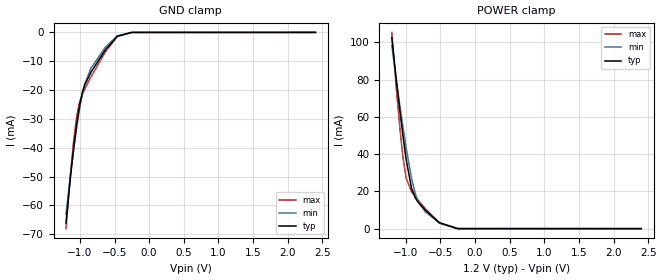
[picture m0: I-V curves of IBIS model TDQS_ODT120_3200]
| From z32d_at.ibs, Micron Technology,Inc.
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| MODEL TDQS_ODT120_3200 (TDQS Terminator Model with 120ohm ODT, 1600-3200Mbps)
[Model]   TDQS_ODT120_3200
Model_type   Terminator
|   typ   min   max
|C_comp   0.616pF   0.564pF   0.668pF
C_comp_power_clamp   0.308pF   0.282pF   0.334pF
C_comp_gnd_clamp   0.308pF   0.282pF   0.334pF
| Note: C_comp changes when the ODT circuit is enabled.
[Voltage Range]   1.2000V   1.1400V   1.2600V
| Junction Temperature (Ambient temp is 35C typ, 105C min, -40C max)
[Temperature Range]   50.0   120.0   -40.0
[Add Submodel]
| Submodel Name   Mode
120ohm_ODT_3200   Non-Driving
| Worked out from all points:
|   GND clamp passes 1 mA (typ) near -0.44 V on its own axis
|   POWER clamp passes 1 mA (typ) near -0.41 V on its own axis
[GND Clamp]
|   Voltage   I(typ)   I(min)   I(max)
-1.2V     -66.16mA   -63.19mA   -68.09mA
-1.135V   -50.09mA   -49.27mA   -48.84mA
-1.091V   -40.54mA   -40.91mA   -37.85mA
-1.047V   -32.06mA   -33.18mA   -29.28mA
-1.004V   -25.24mA   -26.41mA   -24.15mA
-960mV    -20.46mA   -20.87mA   -21.27mA
-927.3mV  -18.11mA   -17.71mA   -19.59mA
-840mV    -13.84mA   -12.43mA   -15.5mA
-632.7mV  -6.06mA    -5.168mA   -6.758mA
-458.2mV  -1.359mA   -1.153mA   -1.332mA
-250.9mV  -9.002uA   -15.24uA   1.741uA
2.4V      0A         0A         0A
[POWER Clamp]
|   Voltage   I(typ)   I(min)   I(max)
-1.2V     102.5mA    98.29mA    105.3mA
-1.135V   79.77mA    79.49mA    75.19mA
-1.08V    62.13mA    64.93mA    52.54mA
-1.036V   48.91mA    53.79mA    37.32mA
-992.7mV  37.04mA    43.27mA    27.02mA
-916.4mV  21.89mA    27.24mA    20mA
-861.8mV  16.57mA    18.83mA    17.26mA
-818.2mV  14.14mA    14.37mA    15.22mA
-720mV    10.08mA    9.153mA    10.86mA
-512.7mV  3.198mA    2.931mA    3.061mA
-250.9mV  21.9uA     40.66uA    -1.736uA
2.4V      0A         0A         0A
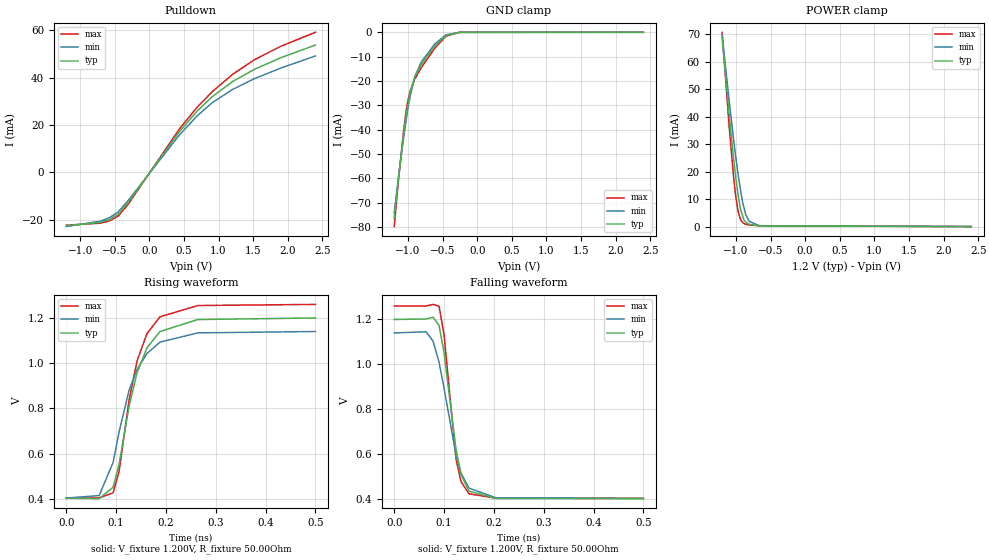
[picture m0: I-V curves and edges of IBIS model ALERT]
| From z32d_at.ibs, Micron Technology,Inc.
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| MODEL ALERT (ALERT_n Output Model, 1600-3200Mbps)
[Model]   ALERT
Model_type   Open_sink
Vmeas = 960.000mV
Vref = 1200.000mV
Cref = 0.0pF
Rref = 50.000Ohm
|   typ   min   max
|C_comp   0.610pF   0.560pF   0.660pF
C_comp_pulldown   0.610pF   0.560pF   0.660pF
[Model Spec]
| Timing spec test load voltage corners
Vref   1.2000V   1.1400V   1.2600V
[Voltage Range]   1.2000V   1.1400V   1.2600V
| Junction Temperature (Ambient temp is 35C typ, 105C min, -40C max)
[Temperature Range]   50.0   120.0   -40.0
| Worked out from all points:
|   slope of the pulldown table from 0 to 0.18 V, typ, clamps not added: 24.5 ohm
|   GND clamp passes 1 mA (typ) near -0.43 V on its own axis
|   POWER clamp passes 1 mA (typ) near -0.83 V on its own axis
|   falling waveform, V_fixture 1.200V, R_fixture 50.00Ohm: 20-80 % time 27.9ps typ, 37.5ps min, 22.3ps max; typ from 1.2 V to 0.402 V
|   rising waveform, V_fixture 1.200V, R_fixture 50.00Ohm: 20-80 % time 49.1ps typ, 53.8ps min, 43.7ps max; typ from 0.402 V to 1.2 V
[Pulldown]
|   Voltage   I(typ)   I(min)   I(max)
-1.2V     -22.54mA   -22.87mA   -22.27mA
-710mV    -21.12mA   -20.6mA    -21.46mA
-570mV    -19.84mA   -19.05mA   -20.41mA
-450mV    -17.65mA   -16.68mA   -18.44mA
-310mV    -12.89mA   -12.03mA   -13.65mA
435mV     17.19mA    15.81mA    18.36mA
690mV     25.85mA    23.84mA    27.49mA
910mV     31.97mA    29.44mA    34.06mA
1.205V    38.38mA    35.04mA    41.41mA
1.52V     43.52mA    39.57mA    47.57mA
1.905V    48.45mA    44.09mA    53.3mA
2.4V      53.74mA    49.14mA    59.12mA
[GND Clamp]
|   Voltage   I(typ)   I(min)   I(max)
-1.2V     -76.4mA    -74.25mA   -79.84mA
-1.135V   -59.09mA   -58.98mA   -59.82mA
-1.07V    -43.25mA   -44.67mA   -41.91mA
-1.035V   -35.61mA   -37.58mA   -33.91mA
-1.005V   -30.19mA   -31.98mA   -28.51mA
-970mV    -24.78mA   -26.43mA   -24.09mA
-905mV    -18.52mA   -18.41mA   -19.37mA
-810mV    -13.26mA   -12.25mA   -14.58mA
-615mV    -5.667mA   -4.803mA   -6.603mA
-450mV    -1.266mA   -1.025mA   -1.56mA
-255mV    -15.46uA   -18.56uA   -16.29uA
2.4V      0A         0A         0A
[POWER Clamp]
|   Voltage   I(typ)   I(min)   I(max)
-1.2V     68.86mA    69.95mA    70.72mA
-1.1V     41.05mA    46.24mA    36.96mA
-1.035V   24.8mA     31.9mA     18.19mA
-1.005V   18.35mA    25.71mA    11.33mA
-970mV    11.69mA    19.19mA    5.58mA
-935mV    6.43mA     13.41mA    2.598mA
-905mV    3.96mA     8.987mA    1.451mA
-885mV    2.429mA    6.991mA    1.136mA
-860mV    1.707mA    4.496mA    842.7uA
-810mV    801.4uA    1.92mA     564uA
-660mV    241.9uA    277.1uA    324.3uA
2.4V      0A         0A         0A
[Ramp]
R_load = 50.00Ohm
|   typ   min   max
dV/dt_r   478.729mV/49.051ps  442.085mV/53.817ps  513.741mV/43.654ps
dV/dt_f   478.729mV/27.886ps  442.085mV/37.537ps  513.741mV/22.329ps
[Falling Waveform]
V_fixture = 1.200V
V_fixture_min = 1.140V
V_fixture_max = 1.260V
R_fixture = 50.00Ohm
|   Time   V(typ)   V(min)   V(max)
0s        1.2V       1.14V      1.26V
64ps      1.202V     1.145V     1.26V
78ps      1.21V      1.103V     1.267V
90ps      1.173V     1.01V      1.259V
100ps     1.053V     894.4mV    1.132V
124ps     621.8mV    597mV      579.3mV
134ps     509.7mV    516.3mV    478.1mV
150ps     436mV      449.3mV    423.8mV
204ps     403.2mV    406.2mV    404.1mV
500ps     402.1mV    403.2mV    403.8mV
[Rising Waveform]
V_fixture = 1.200V
V_fixture_min = 1.140V
V_fixture_max = 1.260V
R_fixture = 50.00Ohm
|   Time   V(typ)   V(min)   V(max)
0s        402.1mV    403.2mV    403.8mV
66ps      400.3mV    414mV      403.3mV
94ps      451.1mV    560.8mV    426.5mV
106ps     552.6mV    696.4mV    521.3mV
126ps     809.7mV    880mV      837.3mV
142ps     957.8mV    972mV      1.01V
162ps     1.068V     1.043V     1.131V
188ps     1.14V      1.093V     1.205V
264ps     1.193V     1.134V     1.255V
500ps     1.2V       1.14V      1.26V
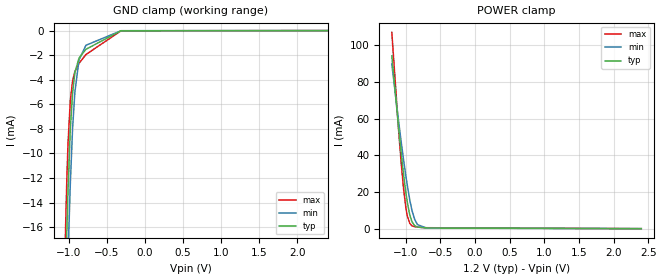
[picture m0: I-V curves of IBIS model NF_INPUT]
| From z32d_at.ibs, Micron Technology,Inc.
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| MODEL NF_INPUT (Non-Functioning Terminator Model)
[Model]   NF_INPUT
Model_type   Terminator
|   typ   min   max
|C_comp   0.362pF   0.312pF   0.412pF
C_comp_power_clamp   0.181pF   0.156pF   0.206pF
C_comp_gnd_clamp   0.181pF   0.156pF   0.206pF
[Voltage Range]   1.2000V   1.1400V   1.2600V
| Junction Temperature (Ambient temp is 35C typ, 105C min, -40C max)
[Temperature Range]   50.0   120.0   -40.0
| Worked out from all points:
|   GND clamp passes 1 mA (typ) near -0.68 V on its own axis
|   POWER clamp passes 1 mA (typ) near -0.84 V on its own axis
[GND Clamp]
|   Voltage   I(typ)   I(min)   I(max)
-1.2V     -75.7mA    -73.15mA   -81.94mA
-1.06V    -25.47mA   -30.15mA   -21.29mA
-1.045V   -21.28mA   -26.41mA   -16.8mA
-1.025V   -16.24mA   -21.42mA   -12.02mA
-1.01V    -13.04mA   -18.29mA   -9.212mA
-980mV    -8.049mA   -12.51mA   -5.739mA
-950mV    -5.074mA   -7.962mA   -4.107mA
-920mV    -3.415mA   -5.011mA   -3.338mA
-865mV    -2.23mA    -2.372mA   -2.662mA
-775mV    -1.523mA   -1.197mA   -1.95mA
-315mV    -13.35uA   -11.28uA   -18.46uA
2.4V      0A         0A         0A
[POWER Clamp]
|   Voltage   I(typ)   I(min)   I(max)
-1.2V     94.24mA    89.76mA    107mA
-1.1V     54.19mA    57.92mA    52.68mA
-1.065V   41.3mA     47.43mA    35.99mA
-1.03V    29.43mA    37.45mA    21.62mA
-995mV    19.04mA    28.15mA    10.83mA
-975mV    14.08mA    23.29mA    6.744mA
-940mV    7.306mA    15.46mA    2.843mA
-910mV    3.836mA    10.08mA    1.58mA
-870mV    1.616mA    5.02mA     1.03mA
-830mV    856.5uA    2.219mA    837.6uA
-700mV    369.3uA    304.1uA    508.7uA
2.4V      0A         0A         0A
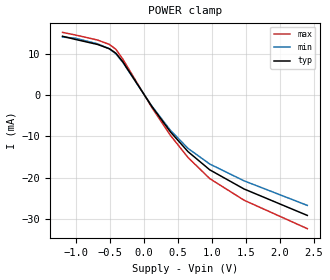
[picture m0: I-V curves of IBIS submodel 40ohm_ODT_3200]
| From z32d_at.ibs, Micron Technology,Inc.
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| SUBMODEL 40ohm_ODT_3200
[Submodel]   40ohm_ODT_3200
Submodel_type  Dynamic_clamp
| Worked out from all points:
|   POWER clamp passes 1 mA (typ) near -0.04 V on its own axis
[POWER Clamp]
|   Voltage   I(typ)   I(min)   I(max)
-1.2V     14.19mA    13.99mA    15.12mA
-1.015V   13.44mA    13.73mA    14.51mA
-685mV    12.21mA    12.37mA    13.28mA
-510mV    11.17mA    11.14mA    12.21mA
-415mV    10.09mA    9.927mA    11.03mA
-315mV    8.073mA    7.911mA    8.719mA
115mV     -2.8mA     -2.701mA   -3.042mA
390mV     -8.967mA   -8.579mA   -9.813mA
645mV     -13.67mA   -12.89mA   -15.08mA
965mV     -18.07mA   -16.67mA   -20.19mA
1.47V     -22.7mA    -20.73mA   -25.41mA
2.4V      -29.08mA   -26.66mA   -32.28mA
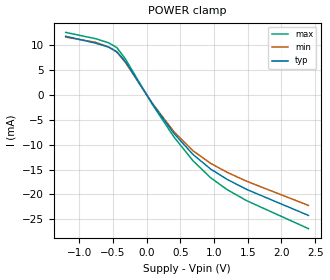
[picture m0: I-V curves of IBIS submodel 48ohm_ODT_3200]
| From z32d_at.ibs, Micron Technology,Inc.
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| SUBMODEL 48ohm_ODT_3200
[Submodel]   48ohm_ODT_3200
Submodel_type  Dynamic_clamp
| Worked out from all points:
|   POWER clamp passes 1 mA (typ) near -0.05 V on its own axis
[POWER Clamp]
|   Voltage   I(typ)   I(min)   I(max)
-1.2V     11.82mA    11.66mA    12.6mA
-755mV    10.43mA    10.6mA     11.33mA
-560mV    9.617mA    9.653mA    10.49mA
-440mV    8.7mA      8.598mA    9.523mA
-315mV    6.729mA    6.587mA    7.263mA
80mV      -1.629mA   -1.578mA   -1.772mA
405mV     -7.727mA   -7.384mA   -8.452mA
685mV     -11.93mA   -11.2mA    -13.19mA
950mV     -14.91mA   -13.76mA   -16.66mA
1.195V    -16.99mA   -15.57mA   -19.05mA
1.485V    -19.01mA   -17.37mA   -21.28mA
2.4V      -24.24mA   -22.22mA   -26.9mA
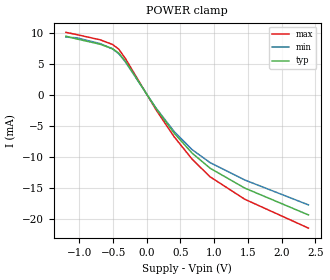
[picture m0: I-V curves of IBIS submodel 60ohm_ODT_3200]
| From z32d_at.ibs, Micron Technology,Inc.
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| SUBMODEL 60ohm_ODT_3200
[Submodel]   60ohm_ODT_3200
Submodel_type  Dynamic_clamp
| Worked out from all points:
|   POWER clamp passes 1 mA (typ) near -0.06 V on its own axis
[POWER Clamp]
|   Voltage   I(typ)   I(min)   I(max)
-1.2V     9.457mA    9.315mA    10.08mA
-1.045V   9.029mA    9.212mA    9.733mA
-695mV    8.171mA    8.28mA     8.886mA
-510mV    7.447mA    7.426mA    8.139mA
-415mV    6.72mA     6.614mA    7.359mA
-315mV    5.383mA    5.273mA    5.811mA
135mV     -2.184mA   -2.107mA   -2.382mA
405mV     -6.175mA   -5.911mA   -6.761mA
670mV     -9.383mA   -8.829mA   -10.36mA
940mV     -11.85mA   -10.95mA   -13.24mA
1.455V    -15.06mA   -13.75mA   -16.86mA
2.4V      -19.39mA   -17.77mA   -21.52mA
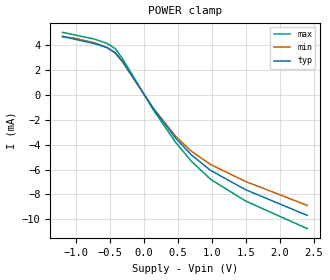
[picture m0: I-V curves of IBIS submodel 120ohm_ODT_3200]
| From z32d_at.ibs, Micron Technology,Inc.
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| SUBMODEL 120ohm_ODT_3200
[Submodel]   120ohm_ODT_3200
Submodel_type  Dynamic_clamp
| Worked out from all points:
|   POWER clamp passes 1 mA (typ) near -0.12 V on its own axis
[POWER Clamp]
|   Voltage   I(typ)   I(min)   I(max)
-1.2V     4.73mA     4.658mA    5.04mA
-1.045V   4.516mA    4.607mA    4.868mA
-730mV    4.137mA    4.2mA      4.498mA
-550mV    3.825mA    3.834mA    4.172mA
-425mV    3.414mA    3.365mA    3.735mA
-320mV    2.733mA    2.677mA    2.952mA
135mV     -1.092mA   -1.054mA   -1.191mA
460mV     -3.449mA   -3.296mA   -3.784mA
695mV     -4.822mA   -4.526mA   -5.336mA
980mV     -6.079mA   -5.603mA   -6.798mA
1.495V    -7.63mA    -6.97mA    -8.542mA
2.4V      -9.695mA   -8.888mA   -10.76mA
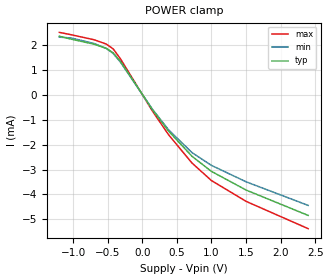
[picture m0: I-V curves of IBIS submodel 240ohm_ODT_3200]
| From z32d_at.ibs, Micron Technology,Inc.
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| SUBMODEL 240ohm_ODT_3200
[Submodel]   240ohm_ODT_3200
Submodel_type  Dynamic_clamp
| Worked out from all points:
|   POWER clamp passes 1 mA (typ) near -0.23 V on its own axis
[POWER Clamp]
|   Voltage   I(typ)   I(min)   I(max)
-1.2V     2.366mA    2.33mA     2.521mA
-1.025V   2.247mA    2.295mA    2.425mA
-695mV    2.044mA    2.071mA    2.223mA
-520mV    1.877mA    1.874mA    2.05mA
-420mV    1.694mA    1.668mA    1.854mA
-315mV    1.347mA    1.319mA    1.454mA
150mV     -604.5uA   -584.2uA   -660.1uA
380mV     -1.451mA   -1.398mA   -1.598mA
720mV     -2.469mA   -2.321mA   -2.741mA
1V        -3.073mA   -2.832mA   -3.442mA
1.505V    -3.829mA   -3.497mA   -4.285mA
2.4V      -4.847mA   -4.444mA   -5.38mA
